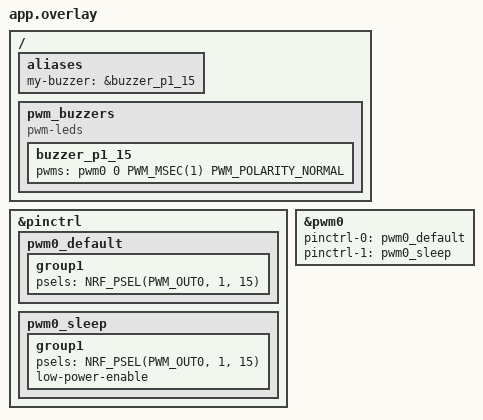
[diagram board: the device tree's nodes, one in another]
#include <zephyr/dt-bindings/pwm/pwm.h>

/ {
    aliases {
        my-buzzer = &buzzer_p1_15;
    };

    pwm_buzzers {
        compatible = "pwm-leds";

        buzzer_p1_15: buzzer_p1_15 {
            pwms = <&pwm0 0 PWM_MSEC(1) PWM_POLARITY_NORMAL>;
        };
    };
};

&pinctrl {
    pwm0_default: pwm0_default {
        group1 {
            psels = <NRF_PSEL(PWM_OUT0, 1, 15)>;
        };
    };

    pwm0_sleep: pwm0_sleep {
        group1 {
            psels = <NRF_PSEL(PWM_OUT0, 1, 15)>;
            low-power-enable;
        };
    };
};

&pwm0 {
    status = "okay";
    pinctrl-0 = <&pwm0_default>;
    pinctrl-1 = <&pwm0_sleep>;
    pinctrl-names = "default", "sleep";
};
